VERSION 5.7 ;
  NOWIREEXTENSIONATPIN ON ;
  DIVIDERCHAR "/" ;
  BUSBITCHARS "[]" ;
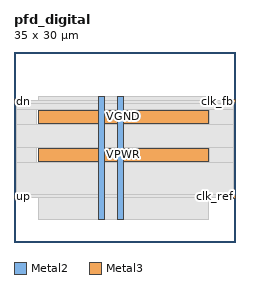
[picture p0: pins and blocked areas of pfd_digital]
MACRO pfd_digital
  CLASS BLOCK ;
  FOREIGN pfd_digital ;
  ORIGIN 0.000 0.000 ;
  SIZE 35.000 BY 30.000 ;
  PIN VGND
    DIRECTION INOUT ;
    USE GROUND ;
    PORT
      LAYER Metal2 ;
        RECT 16.340 3.560 17.340 22.900 ;
    END
    PORT
      LAYER Metal3 ;
        RECT 3.840 18.780 30.720 20.780 ;
    END
  END VGND
  PIN VPWR
    DIRECTION INOUT ;
    USE POWER ;
    PORT
      LAYER Metal2 ;
        RECT 13.340 3.560 14.340 22.900 ;
    END
    PORT
      LAYER Metal3 ;
        RECT 3.840 12.780 30.720 14.780 ;
    END
  END VPWR
  PIN clk_fb
    DIRECTION INPUT ;
    USE SIGNAL ;
    ANTENNAGATEAREA 0.241800 ;
    PORT
      LAYER Metal3 ;
        RECT 34.600 22.060 35.000 22.460 ;
    END
  END clk_fb
  PIN clk_ref
    DIRECTION INPUT ;
    USE SIGNAL ;
    ANTENNAGATEAREA 0.241800 ;
    PORT
      LAYER Metal3 ;
        RECT 34.600 6.940 35.000 7.340 ;
    END
  END clk_ref
  PIN dn
    DIRECTION OUTPUT ;
    USE SIGNAL ;
    ANTENNADIFFAREA 0.708600 ;
    PORT
      LAYER Metal3 ;
        RECT 0.000 22.060 0.400 22.460 ;
    END
  END dn
  PIN up
    DIRECTION OUTPUT ;
    USE SIGNAL ;
    ANTENNADIFFAREA 0.708600 ;
    PORT
      LAYER Metal3 ;
        RECT 0.000 6.940 0.400 7.340 ;
    END
  END up
  OBS
      LAYER GatPoly ;
        RECT 3.840 3.630 30.720 22.830 ;
      LAYER Metal1 ;
        RECT 3.840 3.560 30.720 22.900 ;
      LAYER Metal2 ;
        RECT 4.215 6.995 13.130 22.405 ;
        RECT 14.550 6.995 16.130 22.405 ;
        RECT 17.550 6.995 30.345 22.405 ;
      LAYER Metal3 ;
        RECT 0.610 21.850 34.390 22.360 ;
        RECT 0.400 20.990 34.600 21.850 ;
        RECT 0.400 18.570 3.630 20.990 ;
        RECT 30.930 18.570 34.600 20.990 ;
        RECT 0.400 14.990 34.600 18.570 ;
        RECT 0.400 12.570 3.630 14.990 ;
        RECT 30.930 12.570 34.600 14.990 ;
        RECT 0.400 7.550 34.600 12.570 ;
        RECT 0.610 7.040 34.390 7.550 ;
  END
END pfd_digital
END LIBRARY

